VERSION 5.7 ;
  NOWIREEXTENSIONATPIN ON ;
  DIVIDERCHAR "/" ;
  BUSBITCHARS "[]" ;
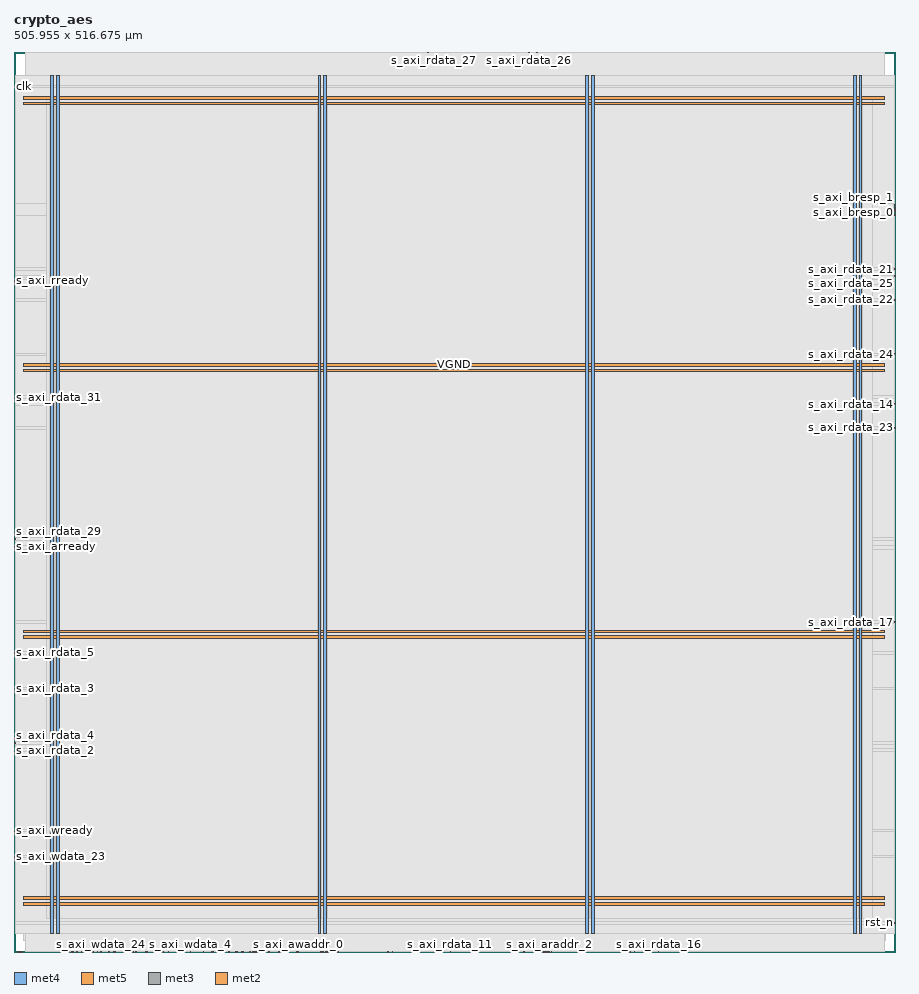
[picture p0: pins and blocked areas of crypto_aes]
MACRO crypto_aes
  CLASS BLOCK ;
  FOREIGN crypto_aes ;
  ORIGIN 0.000 0.000 ;
  SIZE 505.955 BY 516.675 ;
  PIN VGND
    DIRECTION INOUT ;
    USE GROUND ;
    PORT
      LAYER met4 ;
        RECT 24.340 10.640 25.940 503.440 ;
    END
    PORT
      LAYER met4 ;
        RECT 177.940 10.640 179.540 503.440 ;
    END
    PORT
      LAYER met4 ;
        RECT 331.540 10.640 333.140 503.440 ;
    END
    PORT
      LAYER met4 ;
        RECT 485.140 10.640 486.740 503.440 ;
    END
    PORT
      LAYER met5 ;
        RECT 5.520 30.030 500.020 31.630 ;
    END
    PORT
      LAYER met5 ;
        RECT 5.520 183.210 500.020 184.810 ;
    END
    PORT
      LAYER met5 ;
        RECT 5.520 336.390 500.020 337.990 ;
    END
    PORT
      LAYER met5 ;
        RECT 5.520 489.570 500.020 491.170 ;
    END
  END VGND
  PIN VPWR
    DIRECTION INOUT ;
    USE POWER ;
    PORT
      LAYER met4 ;
        RECT 21.040 10.640 22.640 503.440 ;
    END
    PORT
      LAYER met4 ;
        RECT 174.640 10.640 176.240 503.440 ;
    END
    PORT
      LAYER met4 ;
        RECT 328.240 10.640 329.840 503.440 ;
    END
    PORT
      LAYER met4 ;
        RECT 481.840 10.640 483.440 503.440 ;
    END
    PORT
      LAYER met5 ;
        RECT 5.520 26.730 500.020 28.330 ;
    END
    PORT
      LAYER met5 ;
        RECT 5.520 179.910 500.020 181.510 ;
    END
    PORT
      LAYER met5 ;
        RECT 5.520 333.090 500.020 334.690 ;
    END
    PORT
      LAYER met5 ;
        RECT 5.520 486.270 500.020 487.870 ;
    END
  END VPWR
  PIN clk
    DIRECTION INPUT ;
    USE SIGNAL ;
    ANTENNAGATEAREA 1.286700 ;
    ANTENNADIFFAREA 0.434700 ;
    PORT
      LAYER met3 ;
        RECT 0.000 496.440 0.600 497.040 ;
    END
  END clk
  PIN irq
    DIRECTION OUTPUT ;
    USE SIGNAL ;
    ANTENNAGATEAREA 0.434700 ;
    ANTENNADIFFAREA 1.137600 ;
    PORT
      LAYER met3 ;
        RECT 505.355 423.000 505.955 423.600 ;
    END
  END irq
  PIN rst_n
    DIRECTION INPUT ;
    USE SIGNAL ;
    ANTENNAGATEAREA 0.647700 ;
    ANTENNADIFFAREA 0.434700 ;
    PORT
      LAYER met3 ;
        RECT 505.355 16.360 505.955 16.960 ;
    END
  END rst_n
  PIN s_axi_araddr_0
    DIRECTION INPUT ;
    USE SIGNAL ;
    ANTENNAGATEAREA 0.647700 ;
    ANTENNADIFFAREA 0.434700 ;
    PORT
      LAYER met2 ;
        RECT 305.530 0.000 305.810 0.280 ;
    END
  END s_axi_araddr_0
  PIN s_axi_araddr_1
    DIRECTION INPUT ;
    USE SIGNAL ;
    ANTENNAGATEAREA 0.647700 ;
    ANTENNADIFFAREA 0.434700 ;
    PORT
      LAYER met2 ;
        RECT 306.450 0.000 306.730 0.280 ;
    END
  END s_axi_araddr_1
  PIN s_axi_araddr_10
    DIRECTION INPUT ;
    USE SIGNAL ;
    PORT
      LAYER met2 ;
        RECT 1.930 0.000 2.210 0.280 ;
    END
  END s_axi_araddr_10
  PIN s_axi_araddr_11
    DIRECTION INPUT ;
    USE SIGNAL ;
    PORT
      LAYER met2 ;
        RECT 2.850 0.000 3.130 0.280 ;
    END
  END s_axi_araddr_11
  PIN s_axi_araddr_2
    DIRECTION INPUT ;
    USE SIGNAL ;
    ANTENNAGATEAREA 0.647700 ;
    ANTENNADIFFAREA 0.434700 ;
    PORT
      LAYER met2 ;
        RECT 307.370 0.000 307.650 0.280 ;
    END
  END s_axi_araddr_2
  PIN s_axi_araddr_3
    DIRECTION INPUT ;
    USE SIGNAL ;
    ANTENNAGATEAREA 0.647700 ;
    ANTENNADIFFAREA 0.434700 ;
    PORT
      LAYER met2 ;
        RECT 308.290 0.000 308.570 0.280 ;
    END
  END s_axi_araddr_3
  PIN s_axi_araddr_4
    DIRECTION INPUT ;
    USE SIGNAL ;
    ANTENNAGATEAREA 0.647700 ;
    ANTENNADIFFAREA 0.434700 ;
    PORT
      LAYER met2 ;
        RECT 304.610 0.000 304.890 0.280 ;
    END
  END s_axi_araddr_4
  PIN s_axi_araddr_5
    DIRECTION INPUT ;
    USE SIGNAL ;
    ANTENNAGATEAREA 0.647700 ;
    ANTENNADIFFAREA 0.434700 ;
    PORT
      LAYER met2 ;
        RECT 301.850 0.000 302.130 0.280 ;
    END
  END s_axi_araddr_5
  PIN s_axi_araddr_6
    DIRECTION INPUT ;
    USE SIGNAL ;
    ANTENNAGATEAREA 0.647700 ;
    ANTENNADIFFAREA 0.434700 ;
    PORT
      LAYER met2 ;
        RECT 303.690 0.000 303.970 0.280 ;
    END
  END s_axi_araddr_6
  PIN s_axi_araddr_7
    DIRECTION INPUT ;
    USE SIGNAL ;
    ANTENNAGATEAREA 0.647700 ;
    ANTENNADIFFAREA 0.434700 ;
    PORT
      LAYER met2 ;
        RECT 302.770 0.000 303.050 0.280 ;
    END
  END s_axi_araddr_7
  PIN s_axi_araddr_8
    DIRECTION INPUT ;
    USE SIGNAL ;
    PORT
      LAYER met2 ;
        RECT 3.770 0.000 4.050 0.280 ;
    END
  END s_axi_araddr_8
  PIN s_axi_araddr_9
    DIRECTION INPUT ;
    USE SIGNAL ;
    PORT
      LAYER met2 ;
        RECT 4.690 0.000 4.970 0.280 ;
    END
  END s_axi_araddr_9
  PIN s_axi_arready
    DIRECTION OUTPUT ;
    USE SIGNAL ;
    ANTENNAGATEAREA 0.434700 ;
    ANTENNADIFFAREA 1.137600 ;
    PORT
      LAYER met3 ;
        RECT 0.000 232.600 0.600 233.200 ;
    END
  END s_axi_arready
  PIN s_axi_arvalid
    DIRECTION INPUT ;
    USE SIGNAL ;
    ANTENNAGATEAREA 0.647700 ;
    ANTENNADIFFAREA 0.434700 ;
    PORT
      LAYER met3 ;
        RECT 0.000 231.240 0.600 231.840 ;
    END
  END s_axi_arvalid
  PIN s_axi_awaddr_0
    DIRECTION INPUT ;
    USE SIGNAL ;
    ANTENNAGATEAREA 0.647700 ;
    ANTENNADIFFAREA 0.434700 ;
    PORT
      LAYER met2 ;
        RECT 162.930 0.000 163.210 0.280 ;
    END
  END s_axi_awaddr_0
  PIN s_axi_awaddr_1
    DIRECTION INPUT ;
    USE SIGNAL ;
    ANTENNAGATEAREA 0.647700 ;
    ANTENNADIFFAREA 0.434700 ;
    PORT
      LAYER met2 ;
        RECT 162.010 0.000 162.290 0.280 ;
    END
  END s_axi_awaddr_1
  PIN s_axi_awaddr_10
    DIRECTION INPUT ;
    USE SIGNAL ;
    ANTENNAGATEAREA 0.647700 ;
    ANTENNADIFFAREA 0.434700 ;
    PORT
      LAYER met2 ;
        RECT 146.370 0.000 146.650 0.280 ;
    END
  END s_axi_awaddr_10
  PIN s_axi_awaddr_11
    DIRECTION INPUT ;
    USE SIGNAL ;
    ANTENNAGATEAREA 0.647700 ;
    ANTENNADIFFAREA 0.434700 ;
    PORT
      LAYER met2 ;
        RECT 130.730 0.000 131.010 0.280 ;
    END
  END s_axi_awaddr_11
  PIN s_axi_awaddr_2
    DIRECTION INPUT ;
    USE SIGNAL ;
    ANTENNAGATEAREA 0.647700 ;
    ANTENNADIFFAREA 0.434700 ;
    PORT
      LAYER met2 ;
        RECT 154.650 0.000 154.930 0.280 ;
    END
  END s_axi_awaddr_2
  PIN s_axi_awaddr_3
    DIRECTION INPUT ;
    USE SIGNAL ;
    ANTENNAGATEAREA 0.647700 ;
    ANTENNADIFFAREA 0.434700 ;
    PORT
      LAYER met2 ;
        RECT 153.730 0.000 154.010 0.280 ;
    END
  END s_axi_awaddr_3
  PIN s_axi_awaddr_4
    DIRECTION INPUT ;
    USE SIGNAL ;
    ANTENNAGATEAREA 0.647700 ;
    ANTENNADIFFAREA 0.434700 ;
    PORT
      LAYER met2 ;
        RECT 178.570 0.000 178.850 0.280 ;
    END
  END s_axi_awaddr_4
  PIN s_axi_awaddr_5
    DIRECTION INPUT ;
    USE SIGNAL ;
    ANTENNAGATEAREA 0.647700 ;
    ANTENNADIFFAREA 0.434700 ;
    PORT
      LAYER met2 ;
        RECT 180.410 0.000 180.690 0.280 ;
    END
  END s_axi_awaddr_5
  PIN s_axi_awaddr_6
    DIRECTION INPUT ;
    USE SIGNAL ;
    ANTENNAGATEAREA 0.647700 ;
    ANTENNADIFFAREA 0.434700 ;
    PORT
      LAYER met2 ;
        RECT 176.730 0.000 177.010 0.280 ;
    END
  END s_axi_awaddr_6
  PIN s_axi_awaddr_7
    DIRECTION INPUT ;
    USE SIGNAL ;
    ANTENNAGATEAREA 0.647700 ;
    ANTENNADIFFAREA 0.434700 ;
    PORT
      LAYER met2 ;
        RECT 177.650 0.000 177.930 0.280 ;
    END
  END s_axi_awaddr_7
  PIN s_axi_awaddr_8
    DIRECTION INPUT ;
    USE SIGNAL ;
    ANTENNAGATEAREA 0.647700 ;
    ANTENNADIFFAREA 0.434700 ;
    PORT
      LAYER met2 ;
        RECT 139.930 0.000 140.210 0.280 ;
    END
  END s_axi_awaddr_8
  PIN s_axi_awaddr_9
    DIRECTION INPUT ;
    USE SIGNAL ;
    ANTENNAGATEAREA 0.647700 ;
    ANTENNADIFFAREA 0.434700 ;
    PORT
      LAYER met2 ;
        RECT 131.650 0.000 131.930 0.280 ;
    END
  END s_axi_awaddr_9
  PIN s_axi_awready
    DIRECTION OUTPUT ;
    USE SIGNAL ;
    ANTENNAGATEAREA 0.434700 ;
    ANTENNADIFFAREA 1.137600 ;
    PORT
      LAYER met2 ;
        RECT 151.890 0.000 152.170 0.280 ;
    END
  END s_axi_awready
  PIN s_axi_awvalid
    DIRECTION INPUT ;
    USE SIGNAL ;
    ANTENNAGATEAREA 0.647700 ;
    ANTENNADIFFAREA 0.434700 ;
    PORT
      LAYER met2 ;
        RECT 139.010 0.000 139.290 0.280 ;
    END
  END s_axi_awvalid
  PIN s_axi_bready
    DIRECTION INPUT ;
    USE SIGNAL ;
    ANTENNAGATEAREA 0.647700 ;
    ANTENNADIFFAREA 0.434700 ;
    PORT
      LAYER met2 ;
        RECT 135.330 0.000 135.610 0.280 ;
    END
  END s_axi_bready
  PIN s_axi_bresp_0
    DIRECTION OUTPUT ;
    USE SIGNAL ;
    ANTENNAGATEAREA 0.434700 ;
    ANTENNADIFFAREA 0.434700 ;
    PORT
      LAYER met3 ;
        RECT 505.355 424.360 505.955 424.960 ;
    END
  END s_axi_bresp_0
  PIN s_axi_bresp_1
    DIRECTION OUTPUT ;
    USE SIGNAL ;
    ANTENNAGATEAREA 0.434700 ;
    ANTENNADIFFAREA 0.775300 ;
    PORT
      LAYER met3 ;
        RECT 505.355 428.440 505.955 429.040 ;
    END
  END s_axi_bresp_1
  PIN s_axi_bvalid
    DIRECTION OUTPUT ;
    USE SIGNAL ;
    ANTENNAGATEAREA 0.434700 ;
    ANTENNADIFFAREA 1.137600 ;
    PORT
      LAYER met2 ;
        RECT 127.970 0.000 128.250 0.280 ;
    END
  END s_axi_bvalid
  PIN s_axi_rdata_0
    DIRECTION OUTPUT ;
    USE SIGNAL ;
    ANTENNAGATEAREA 0.434700 ;
    ANTENNADIFFAREA 1.137600 ;
    PORT
      LAYER met2 ;
        RECT 175.810 0.000 176.090 0.280 ;
    END
  END s_axi_rdata_0
  PIN s_axi_rdata_1
    DIRECTION OUTPUT ;
    USE SIGNAL ;
    ANTENNAGATEAREA 0.434700 ;
    ANTENNADIFFAREA 1.137600 ;
    PORT
      LAYER met2 ;
        RECT 265.050 0.000 265.330 0.280 ;
    END
  END s_axi_rdata_1
  PIN s_axi_rdata_10
    DIRECTION OUTPUT ;
    USE SIGNAL ;
    ANTENNAGATEAREA 0.434700 ;
    ANTENNADIFFAREA 1.137600 ;
    PORT
      LAYER met2 ;
        RECT 353.370 0.000 353.650 0.280 ;
    END
  END s_axi_rdata_10
  PIN s_axi_rdata_11
    DIRECTION OUTPUT ;
    USE SIGNAL ;
    ANTENNAGATEAREA 0.434700 ;
    ANTENNADIFFAREA 1.137600 ;
    PORT
      LAYER met2 ;
        RECT 250.330 0.000 250.610 0.280 ;
    END
  END s_axi_rdata_11
  PIN s_axi_rdata_12
    DIRECTION OUTPUT ;
    USE SIGNAL ;
    ANTENNAGATEAREA 0.434700 ;
    ANTENNADIFFAREA 1.137600 ;
    PORT
      LAYER met2 ;
        RECT 179.490 0.000 179.770 0.280 ;
    END
  END s_axi_rdata_12
  PIN s_axi_rdata_13
    DIRECTION OUTPUT ;
    USE SIGNAL ;
    ANTENNAGATEAREA 0.434700 ;
    ANTENNADIFFAREA 1.137600 ;
    PORT
      LAYER met2 ;
        RECT 356.130 0.000 356.410 0.280 ;
    END
  END s_axi_rdata_13
  PIN s_axi_rdata_14
    DIRECTION OUTPUT ;
    USE SIGNAL ;
    ANTENNAGATEAREA 0.434700 ;
    ANTENNADIFFAREA 1.137600 ;
    PORT
      LAYER met3 ;
        RECT 505.355 314.200 505.955 314.800 ;
    END
  END s_axi_rdata_14
  PIN s_axi_rdata_15
    DIRECTION OUTPUT ;
    USE SIGNAL ;
    ANTENNAGATEAREA 0.434700 ;
    ANTENNADIFFAREA 1.137600 ;
    PORT
      LAYER met2 ;
        RECT 214.450 0.000 214.730 0.280 ;
    END
  END s_axi_rdata_15
  PIN s_axi_rdata_16
    DIRECTION OUTPUT ;
    USE SIGNAL ;
    ANTENNAGATEAREA 0.434700 ;
    ANTENNADIFFAREA 1.137600 ;
    PORT
      LAYER met2 ;
        RECT 369.930 0.000 370.210 0.280 ;
    END
  END s_axi_rdata_16
  PIN s_axi_rdata_17
    DIRECTION OUTPUT ;
    USE SIGNAL ;
    ANTENNAGATEAREA 0.434700 ;
    ANTENNADIFFAREA 1.137600 ;
    PORT
      LAYER met3 ;
        RECT 505.355 189.080 505.955 189.680 ;
    END
  END s_axi_rdata_17
  PIN s_axi_rdata_18
    DIRECTION OUTPUT ;
    USE SIGNAL ;
    ANTENNAGATEAREA 0.434700 ;
    ANTENNADIFFAREA 1.137600 ;
    PORT
      LAYER met2 ;
        RECT 286.210 0.000 286.490 0.280 ;
    END
  END s_axi_rdata_18
  PIN s_axi_rdata_19
    DIRECTION OUTPUT ;
    USE SIGNAL ;
    ANTENNAGATEAREA 0.434700 ;
    ANTENNADIFFAREA 1.137600 ;
    PORT
      LAYER met2 ;
        RECT 245.730 0.000 246.010 0.280 ;
    END
  END s_axi_rdata_19
  PIN s_axi_rdata_2
    DIRECTION OUTPUT ;
    USE SIGNAL ;
    ANTENNAGATEAREA 0.434700 ;
    ANTENNADIFFAREA 1.137600 ;
    PORT
      LAYER met3 ;
        RECT 0.000 115.640 0.600 116.240 ;
    END
  END s_axi_rdata_2
  PIN s_axi_rdata_20
    DIRECTION OUTPUT ;
    USE SIGNAL ;
    ANTENNAGATEAREA 0.434700 ;
    ANTENNADIFFAREA 1.137600 ;
    PORT
      LAYER met2 ;
        RECT 292.650 0.000 292.930 0.280 ;
    END
  END s_axi_rdata_20
  PIN s_axi_rdata_21
    DIRECTION OUTPUT ;
    USE SIGNAL ;
    ANTENNAGATEAREA 0.434700 ;
    ANTENNADIFFAREA 1.137600 ;
    PORT
      LAYER met3 ;
        RECT 505.355 391.720 505.955 392.320 ;
    END
  END s_axi_rdata_21
  PIN s_axi_rdata_22
    DIRECTION OUTPUT ;
    USE SIGNAL ;
    ANTENNAGATEAREA 0.434700 ;
    ANTENNADIFFAREA 1.137600 ;
    PORT
      LAYER met3 ;
        RECT 505.355 374.040 505.955 374.640 ;
    END
  END s_axi_rdata_22
  PIN s_axi_rdata_23
    DIRECTION OUTPUT ;
    USE SIGNAL ;
    ANTENNAGATEAREA 0.434700 ;
    ANTENNADIFFAREA 1.137600 ;
    PORT
      LAYER met3 ;
        RECT 505.355 300.600 505.955 301.200 ;
    END
  END s_axi_rdata_23
  PIN s_axi_rdata_24
    DIRECTION OUTPUT ;
    USE SIGNAL ;
    ANTENNAGATEAREA 0.434700 ;
    ANTENNADIFFAREA 1.137600 ;
    PORT
      LAYER met3 ;
        RECT 505.355 342.760 505.955 343.360 ;
    END
  END s_axi_rdata_24
  PIN s_axi_rdata_25
    DIRECTION OUTPUT ;
    USE SIGNAL ;
    ANTENNAGATEAREA 0.434700 ;
    ANTENNADIFFAREA 1.137600 ;
    PORT
      LAYER met3 ;
        RECT 505.355 387.640 505.955 388.240 ;
    END
  END s_axi_rdata_25
  PIN s_axi_rdata_26
    DIRECTION OUTPUT ;
    USE SIGNAL ;
    ANTENNAGATEAREA 0.434700 ;
    ANTENNADIFFAREA 1.137600 ;
    PORT
      LAYER met2 ;
        RECT 295.410 516.395 295.690 516.675 ;
    END
  END s_axi_rdata_26
  PIN s_axi_rdata_27
    DIRECTION OUTPUT ;
    USE SIGNAL ;
    ANTENNAGATEAREA 0.434700 ;
    ANTENNADIFFAREA 1.137600 ;
    PORT
      LAYER met2 ;
        RECT 241.130 516.395 241.410 516.675 ;
    END
  END s_axi_rdata_27
  PIN s_axi_rdata_28
    DIRECTION OUTPUT ;
    USE SIGNAL ;
    ANTENNAGATEAREA 0.434700 ;
    ANTENNADIFFAREA 1.137600 ;
    PORT
      LAYER met2 ;
        RECT 196.970 516.395 197.250 516.675 ;
    END
  END s_axi_rdata_28
  PIN s_axi_rdata_29
    DIRECTION OUTPUT ;
    USE SIGNAL ;
    ANTENNAGATEAREA 0.434700 ;
    ANTENNADIFFAREA 1.137600 ;
    PORT
      LAYER met3 ;
        RECT 0.000 236.680 0.600 237.280 ;
    END
  END s_axi_rdata_29
  PIN s_axi_rdata_3
    DIRECTION OUTPUT ;
    USE SIGNAL ;
    ANTENNAGATEAREA 0.434700 ;
    ANTENNADIFFAREA 1.137600 ;
    PORT
      LAYER met3 ;
        RECT 0.000 151.000 0.600 151.600 ;
    END
  END s_axi_rdata_3
  PIN s_axi_rdata_30
    DIRECTION OUTPUT ;
    USE SIGNAL ;
    ANTENNAGATEAREA 0.434700 ;
    ANTENNADIFFAREA 1.137600 ;
    PORT
      LAYER met3 ;
        RECT 0.000 383.560 0.600 384.160 ;
    END
  END s_axi_rdata_30
  PIN s_axi_rdata_31
    DIRECTION OUTPUT ;
    USE SIGNAL ;
    ANTENNAGATEAREA 0.434700 ;
    ANTENNADIFFAREA 1.137600 ;
    PORT
      LAYER met3 ;
        RECT 0.000 318.280 0.600 318.880 ;
    END
  END s_axi_rdata_31
  PIN s_axi_rdata_4
    DIRECTION OUTPUT ;
    USE SIGNAL ;
    ANTENNAGATEAREA 0.434700 ;
    ANTENNADIFFAREA 1.137600 ;
    PORT
      LAYER met3 ;
        RECT 0.000 119.720 0.600 120.320 ;
    END
  END s_axi_rdata_4
  PIN s_axi_rdata_5
    DIRECTION OUTPUT ;
    USE SIGNAL ;
    ANTENNAGATEAREA 0.434700 ;
    ANTENNADIFFAREA 1.137600 ;
    PORT
      LAYER met3 ;
        RECT 0.000 171.400 0.600 172.000 ;
    END
  END s_axi_rdata_5
  PIN s_axi_rdata_6
    DIRECTION OUTPUT ;
    USE SIGNAL ;
    ANTENNAGATEAREA 0.434700 ;
    ANTENNADIFFAREA 1.137600 ;
    PORT
      LAYER met2 ;
        RECT 237.450 516.395 237.730 516.675 ;
    END
  END s_axi_rdata_6
  PIN s_axi_rdata_7
    DIRECTION OUTPUT ;
    USE SIGNAL ;
    ANTENNAGATEAREA 0.434700 ;
    ANTENNADIFFAREA 1.137600 ;
    PORT
      LAYER met2 ;
        RECT 217.210 0.000 217.490 0.280 ;
    END
  END s_axi_rdata_7
  PIN s_axi_rdata_8
    DIRECTION OUTPUT ;
    USE SIGNAL ;
    ANTENNAGATEAREA 0.434700 ;
    ANTENNADIFFAREA 1.137600 ;
    PORT
      LAYER met2 ;
        RECT 300.010 516.395 300.290 516.675 ;
    END
  END s_axi_rdata_8
  PIN s_axi_rdata_9
    DIRECTION OUTPUT ;
    USE SIGNAL ;
    ANTENNAGATEAREA 0.434700 ;
    ANTENNADIFFAREA 1.137600 ;
    PORT
      LAYER met2 ;
        RECT 288.970 0.000 289.250 0.280 ;
    END
  END s_axi_rdata_9
  PIN s_axi_rready
    DIRECTION INPUT ;
    USE SIGNAL ;
    ANTENNAGATEAREA 0.647700 ;
    ANTENNADIFFAREA 0.434700 ;
    PORT
      LAYER met3 ;
        RECT 0.000 384.920 0.600 385.520 ;
    END
  END s_axi_rready
  PIN s_axi_rresp_0
    DIRECTION OUTPUT ;
    USE SIGNAL ;
    ANTENNAGATEAREA 0.434700 ;
    ANTENNADIFFAREA 0.775300 ;
    PORT
      LAYER met3 ;
        RECT 505.355 425.720 505.955 426.320 ;
    END
  END s_axi_rresp_0
  PIN s_axi_rresp_1
    DIRECTION OUTPUT ;
    USE SIGNAL ;
    ANTENNAGATEAREA 0.434700 ;
    ANTENNADIFFAREA 0.775300 ;
    PORT
      LAYER met3 ;
        RECT 505.355 427.080 505.955 427.680 ;
    END
  END s_axi_rresp_1
  PIN s_axi_rvalid
    DIRECTION OUTPUT ;
    USE SIGNAL ;
    ANTENNAGATEAREA 0.434700 ;
    ANTENNADIFFAREA 1.137600 ;
    PORT
      LAYER met2 ;
        RECT 185.930 0.000 186.210 0.280 ;
    END
  END s_axi_rvalid
  PIN s_axi_wdata_0
    DIRECTION INPUT ;
    USE SIGNAL ;
    ANTENNAGATEAREA 0.647700 ;
    ANTENNADIFFAREA 0.434700 ;
    PORT
      LAYER met2 ;
        RECT 140.850 0.000 141.130 0.280 ;
    END
  END s_axi_wdata_0
  PIN s_axi_wdata_1
    DIRECTION INPUT ;
    USE SIGNAL ;
    ANTENNAGATEAREA 0.647700 ;
    ANTENNADIFFAREA 0.434700 ;
    PORT
      LAYER met2 ;
        RECT 142.690 0.000 142.970 0.280 ;
    END
  END s_axi_wdata_1
  PIN s_axi_wdata_10
    DIRECTION INPUT ;
    USE SIGNAL ;
    ANTENNAGATEAREA 0.647700 ;
    ANTENNADIFFAREA 0.434700 ;
    PORT
      LAYER met2 ;
        RECT 57.130 0.000 57.410 0.280 ;
    END
  END s_axi_wdata_10
  PIN s_axi_wdata_11
    DIRECTION INPUT ;
    USE SIGNAL ;
    ANTENNAGATEAREA 0.647700 ;
    ANTENNADIFFAREA 0.434700 ;
    PORT
      LAYER met2 ;
        RECT 47.930 0.000 48.210 0.280 ;
    END
  END s_axi_wdata_11
  PIN s_axi_wdata_12
    DIRECTION INPUT ;
    USE SIGNAL ;
    ANTENNAGATEAREA 0.647700 ;
    ANTENNADIFFAREA 0.434700 ;
    PORT
      LAYER met2 ;
        RECT 70.010 0.000 70.290 0.280 ;
    END
  END s_axi_wdata_12
  PIN s_axi_wdata_13
    DIRECTION INPUT ;
    USE SIGNAL ;
    ANTENNAGATEAREA 0.647700 ;
    ANTENNADIFFAREA 0.434700 ;
    PORT
      LAYER met2 ;
        RECT 88.410 0.000 88.690 0.280 ;
    END
  END s_axi_wdata_13
  PIN s_axi_wdata_14
    DIRECTION INPUT ;
    USE SIGNAL ;
    ANTENNAGATEAREA 0.647700 ;
    ANTENNADIFFAREA 0.434700 ;
    PORT
      LAYER met2 ;
        RECT 84.730 0.000 85.010 0.280 ;
    END
  END s_axi_wdata_14
  PIN s_axi_wdata_15
    DIRECTION INPUT ;
    USE SIGNAL ;
    ANTENNAGATEAREA 0.647700 ;
    ANTENNADIFFAREA 0.434700 ;
    PORT
      LAYER met2 ;
        RECT 40.570 0.000 40.850 0.280 ;
    END
  END s_axi_wdata_15
  PIN s_axi_wdata_16
    DIRECTION INPUT ;
    USE SIGNAL ;
    ANTENNAGATEAREA 0.647700 ;
    ANTENNADIFFAREA 0.434700 ;
    PORT
      LAYER met2 ;
        RECT 123.370 0.000 123.650 0.280 ;
    END
  END s_axi_wdata_16
  PIN s_axi_wdata_17
    DIRECTION INPUT ;
    USE SIGNAL ;
    ANTENNAGATEAREA 0.647700 ;
    ANTENNADIFFAREA 0.434700 ;
    PORT
      LAYER met2 ;
        RECT 35.970 0.000 36.250 0.280 ;
    END
  END s_axi_wdata_17
  PIN s_axi_wdata_18
    DIRECTION INPUT ;
    USE SIGNAL ;
    ANTENNAGATEAREA 0.647700 ;
    ANTENNADIFFAREA 0.434700 ;
    PORT
      LAYER met2 ;
        RECT 108.650 0.000 108.930 0.280 ;
    END
  END s_axi_wdata_18
  PIN s_axi_wdata_19
    DIRECTION INPUT ;
    USE SIGNAL ;
    ANTENNAGATEAREA 0.647700 ;
    ANTENNADIFFAREA 0.434700 ;
    PORT
      LAYER met2 ;
        RECT 97.610 0.000 97.890 0.280 ;
    END
  END s_axi_wdata_19
  PIN s_axi_wdata_2
    DIRECTION INPUT ;
    USE SIGNAL ;
    ANTENNAGATEAREA 0.647700 ;
    ANTENNADIFFAREA 0.434700 ;
    PORT
      LAYER met2 ;
        RECT 137.170 0.000 137.450 0.280 ;
    END
  END s_axi_wdata_2
  PIN s_axi_wdata_20
    DIRECTION INPUT ;
    USE SIGNAL ;
    ANTENNAGATEAREA 0.647700 ;
    ANTENNADIFFAREA 0.434700 ;
    PORT
      LAYER met2 ;
        RECT 54.370 0.000 54.650 0.280 ;
    END
  END s_axi_wdata_20
  PIN s_axi_wdata_21
    DIRECTION INPUT ;
    USE SIGNAL ;
    ANTENNAGATEAREA 0.647700 ;
    ANTENNADIFFAREA 0.434700 ;
    PORT
      LAYER met2 ;
        RECT 62.650 0.000 62.930 0.280 ;
    END
  END s_axi_wdata_21
  PIN s_axi_wdata_22
    DIRECTION INPUT ;
    USE SIGNAL ;
    ANTENNAGATEAREA 0.647700 ;
    ANTENNADIFFAREA 0.434700 ;
    PORT
      LAYER met2 ;
        RECT 85.650 0.000 85.930 0.280 ;
    END
  END s_axi_wdata_22
  PIN s_axi_wdata_23
    DIRECTION INPUT ;
    USE SIGNAL ;
    ANTENNAGATEAREA 0.647700 ;
    ANTENNADIFFAREA 0.434700 ;
    PORT
      LAYER met3 ;
        RECT 0.000 54.440 0.600 55.040 ;
    END
  END s_axi_wdata_23
  PIN s_axi_wdata_24
    DIRECTION INPUT ;
    USE SIGNAL ;
    ANTENNAGATEAREA 0.647700 ;
    ANTENNADIFFAREA 0.434700 ;
    PORT
      LAYER met2 ;
        RECT 49.770 0.000 50.050 0.280 ;
    END
  END s_axi_wdata_24
  PIN s_axi_wdata_25
    DIRECTION INPUT ;
    USE SIGNAL ;
    ANTENNAGATEAREA 0.647700 ;
    ANTENNADIFFAREA 0.434700 ;
    PORT
      LAYER met2 ;
        RECT 45.170 0.000 45.450 0.280 ;
    END
  END s_axi_wdata_25
  PIN s_axi_wdata_26
    DIRECTION INPUT ;
    USE SIGNAL ;
    ANTENNAGATEAREA 0.647700 ;
    ANTENNADIFFAREA 0.434700 ;
    PORT
      LAYER met2 ;
        RECT 113.250 0.000 113.530 0.280 ;
    END
  END s_axi_wdata_26
  PIN s_axi_wdata_27
    DIRECTION INPUT ;
    USE SIGNAL ;
    ANTENNAGATEAREA 0.647700 ;
    ANTENNADIFFAREA 0.434700 ;
    PORT
      LAYER met2 ;
        RECT 38.730 0.000 39.010 0.280 ;
    END
  END s_axi_wdata_27
  PIN s_axi_wdata_28
    DIRECTION INPUT ;
    USE SIGNAL ;
    ANTENNAGATEAREA 0.647700 ;
    ANTENNADIFFAREA 0.434700 ;
    PORT
      LAYER met2 ;
        RECT 117.850 0.000 118.130 0.280 ;
    END
  END s_axi_wdata_28
  PIN s_axi_wdata_29
    DIRECTION INPUT ;
    USE SIGNAL ;
    ANTENNAGATEAREA 0.647700 ;
    ANTENNADIFFAREA 0.434700 ;
    PORT
      LAYER met2 ;
        RECT 114.170 0.000 114.450 0.280 ;
    END
  END s_axi_wdata_29
  PIN s_axi_wdata_3
    DIRECTION INPUT ;
    USE SIGNAL ;
    ANTENNAGATEAREA 0.647700 ;
    ANTENNADIFFAREA 0.434700 ;
    PORT
      LAYER met2 ;
        RECT 43.330 0.000 43.610 0.280 ;
    END
  END s_axi_wdata_3
  PIN s_axi_wdata_30
    DIRECTION INPUT ;
    USE SIGNAL ;
    ANTENNAGATEAREA 0.647700 ;
    ANTENNADIFFAREA 0.434700 ;
    PORT
      LAYER met2 ;
        RECT 34.130 0.000 34.410 0.280 ;
    END
  END s_axi_wdata_30
  PIN s_axi_wdata_31
    DIRECTION INPUT ;
    USE SIGNAL ;
    ANTENNAGATEAREA 0.647700 ;
    ANTENNADIFFAREA 0.434700 ;
    PORT
      LAYER met2 ;
        RECT 81.970 0.000 82.250 0.280 ;
    END
  END s_axi_wdata_31
  PIN s_axi_wdata_4
    DIRECTION INPUT ;
    USE SIGNAL ;
    ANTENNAGATEAREA 0.647700 ;
    ANTENNADIFFAREA 0.434700 ;
    PORT
      LAYER met2 ;
        RECT 101.290 0.000 101.570 0.280 ;
    END
  END s_axi_wdata_4
  PIN s_axi_wdata_5
    DIRECTION INPUT ;
    USE SIGNAL ;
    ANTENNAGATEAREA 0.647700 ;
    ANTENNADIFFAREA 0.434700 ;
    PORT
      LAYER met2 ;
        RECT 58.050 0.000 58.330 0.280 ;
    END
  END s_axi_wdata_5
  PIN s_axi_wdata_6
    DIRECTION INPUT ;
    USE SIGNAL ;
    ANTENNAGATEAREA 0.647700 ;
    ANTENNADIFFAREA 0.434700 ;
    PORT
      LAYER met2 ;
        RECT 75.530 0.000 75.810 0.280 ;
    END
  END s_axi_wdata_6
  PIN s_axi_wdata_7
    DIRECTION INPUT ;
    USE SIGNAL ;
    ANTENNAGATEAREA 0.647700 ;
    ANTENNADIFFAREA 0.434700 ;
    PORT
      LAYER met2 ;
        RECT 65.410 0.000 65.690 0.280 ;
    END
  END s_axi_wdata_7
  PIN s_axi_wdata_8
    DIRECTION INPUT ;
    USE SIGNAL ;
    ANTENNAGATEAREA 0.647700 ;
    ANTENNADIFFAREA 0.434700 ;
    PORT
      LAYER met2 ;
        RECT 76.450 0.000 76.730 0.280 ;
    END
  END s_axi_wdata_8
  PIN s_axi_wdata_9
    DIRECTION INPUT ;
    USE SIGNAL ;
    ANTENNAGATEAREA 0.647700 ;
    ANTENNADIFFAREA 0.434700 ;
    PORT
      LAYER met2 ;
        RECT 33.210 0.000 33.490 0.280 ;
    END
  END s_axi_wdata_9
  PIN s_axi_wready
    DIRECTION OUTPUT ;
    USE SIGNAL ;
    ANTENNAGATEAREA 0.434700 ;
    ANTENNADIFFAREA 1.137600 ;
    PORT
      LAYER met3 ;
        RECT 0.000 69.400 0.600 70.000 ;
    END
  END s_axi_wready
  PIN s_axi_wstrb_0
    DIRECTION INPUT ;
    USE SIGNAL ;
    ANTENNAGATEAREA 0.647700 ;
    ANTENNADIFFAREA 0.434700 ;
    PORT
      LAYER met2 ;
        RECT 138.090 0.000 138.370 0.280 ;
    END
  END s_axi_wstrb_0
  PIN s_axi_wstrb_1
    DIRECTION INPUT ;
    USE SIGNAL ;
    ANTENNAGATEAREA 0.647700 ;
    ANTENNADIFFAREA 0.434700 ;
    PORT
      LAYER met2 ;
        RECT 68.170 0.000 68.450 0.280 ;
    END
  END s_axi_wstrb_1
  PIN s_axi_wstrb_2
    DIRECTION INPUT ;
    USE SIGNAL ;
    ANTENNAGATEAREA 0.647700 ;
    ANTENNADIFFAREA 0.434700 ;
    PORT
      LAYER met2 ;
        RECT 63.570 0.000 63.850 0.280 ;
    END
  END s_axi_wstrb_2
  PIN s_axi_wstrb_3
    DIRECTION INPUT ;
    USE SIGNAL ;
    ANTENNAGATEAREA 0.647700 ;
    ANTENNADIFFAREA 0.434700 ;
    PORT
      LAYER met2 ;
        RECT 31.370 0.000 31.650 0.280 ;
    END
  END s_axi_wstrb_3
  PIN s_axi_wvalid
    DIRECTION INPUT ;
    USE SIGNAL ;
    ANTENNAGATEAREA 0.647700 ;
    ANTENNADIFFAREA 0.434700 ;
    PORT
      LAYER met2 ;
        RECT 127.050 0.000 127.330 0.280 ;
    END
  END s_axi_wvalid
  OBS
      LAYER nwell ;
        RECT 5.330 10.795 500.210 503.390 ;
      LAYER li1 ;
        RECT 5.520 10.795 500.020 503.285 ;
      LAYER met1 ;
        RECT 5.520 6.500 500.320 503.440 ;
      LAYER met2 ;
        RECT 6.530 516.115 196.690 516.395 ;
        RECT 197.530 516.115 237.170 516.395 ;
        RECT 238.010 516.115 240.850 516.395 ;
        RECT 241.690 516.115 295.130 516.395 ;
        RECT 295.970 516.115 299.730 516.395 ;
        RECT 300.570 516.115 499.460 516.395 ;
        RECT 6.530 0.560 499.460 516.115 ;
        RECT 6.530 0.070 31.090 0.560 ;
        RECT 31.930 0.070 32.930 0.560 ;
        RECT 33.770 0.070 33.850 0.560 ;
        RECT 34.690 0.070 35.690 0.560 ;
        RECT 36.530 0.070 38.450 0.560 ;
        RECT 39.290 0.070 40.290 0.560 ;
        RECT 41.130 0.070 43.050 0.560 ;
        RECT 43.890 0.070 44.890 0.560 ;
        RECT 45.730 0.070 47.650 0.560 ;
        RECT 48.490 0.070 49.490 0.560 ;
        RECT 50.330 0.070 54.090 0.560 ;
        RECT 54.930 0.070 56.850 0.560 ;
        RECT 57.690 0.070 57.770 0.560 ;
        RECT 58.610 0.070 62.370 0.560 ;
        RECT 63.210 0.070 63.290 0.560 ;
        RECT 64.130 0.070 65.130 0.560 ;
        RECT 65.970 0.070 67.890 0.560 ;
        RECT 68.730 0.070 69.730 0.560 ;
        RECT 70.570 0.070 75.250 0.560 ;
        RECT 76.090 0.070 76.170 0.560 ;
        RECT 77.010 0.070 81.690 0.560 ;
        RECT 82.530 0.070 84.450 0.560 ;
        RECT 85.290 0.070 85.370 0.560 ;
        RECT 86.210 0.070 88.130 0.560 ;
        RECT 88.970 0.070 97.330 0.560 ;
        RECT 98.170 0.070 101.010 0.560 ;
        RECT 101.850 0.070 108.370 0.560 ;
        RECT 109.210 0.070 112.970 0.560 ;
        RECT 113.810 0.070 113.890 0.560 ;
        RECT 114.730 0.070 117.570 0.560 ;
        RECT 118.410 0.070 123.090 0.560 ;
        RECT 123.930 0.070 126.770 0.560 ;
        RECT 127.610 0.070 127.690 0.560 ;
        RECT 128.530 0.070 130.450 0.560 ;
        RECT 131.290 0.070 131.370 0.560 ;
        RECT 132.210 0.070 135.050 0.560 ;
        RECT 135.890 0.070 136.890 0.560 ;
        RECT 137.730 0.070 137.810 0.560 ;
        RECT 138.650 0.070 138.730 0.560 ;
        RECT 139.570 0.070 139.650 0.560 ;
        RECT 140.490 0.070 140.570 0.560 ;
        RECT 141.410 0.070 142.410 0.560 ;
        RECT 143.250 0.070 146.090 0.560 ;
        RECT 146.930 0.070 151.610 0.560 ;
        RECT 152.450 0.070 153.450 0.560 ;
        RECT 154.290 0.070 154.370 0.560 ;
        RECT 155.210 0.070 161.730 0.560 ;
        RECT 162.570 0.070 162.650 0.560 ;
        RECT 163.490 0.070 175.530 0.560 ;
        RECT 176.370 0.070 176.450 0.560 ;
        RECT 177.290 0.070 177.370 0.560 ;
        RECT 178.210 0.070 178.290 0.560 ;
        RECT 179.130 0.070 179.210 0.560 ;
        RECT 180.050 0.070 180.130 0.560 ;
        RECT 180.970 0.070 185.650 0.560 ;
        RECT 186.490 0.070 214.170 0.560 ;
        RECT 215.010 0.070 216.930 0.560 ;
        RECT 217.770 0.070 245.450 0.560 ;
        RECT 246.290 0.070 250.050 0.560 ;
        RECT 250.890 0.070 264.770 0.560 ;
        RECT 265.610 0.070 285.930 0.560 ;
        RECT 286.770 0.070 288.690 0.560 ;
        RECT 289.530 0.070 292.370 0.560 ;
        RECT 293.210 0.070 301.570 0.560 ;
        RECT 302.410 0.070 302.490 0.560 ;
        RECT 303.330 0.070 303.410 0.560 ;
        RECT 304.250 0.070 304.330 0.560 ;
        RECT 305.170 0.070 305.250 0.560 ;
        RECT 306.090 0.070 306.170 0.560 ;
        RECT 307.010 0.070 307.090 0.560 ;
        RECT 307.930 0.070 308.010 0.560 ;
        RECT 308.850 0.070 353.090 0.560 ;
        RECT 353.930 0.070 355.850 0.560 ;
        RECT 356.690 0.070 369.650 0.560 ;
        RECT 370.490 0.070 499.460 0.560 ;
      LAYER met3 ;
        RECT 0.600 497.440 505.355 503.365 ;
        RECT 1.000 496.040 505.355 497.440 ;
        RECT 0.600 429.440 505.355 496.040 ;
        RECT 0.600 422.600 504.955 429.440 ;
        RECT 0.600 392.720 505.355 422.600 ;
        RECT 0.600 391.320 504.955 392.720 ;
        RECT 0.600 388.640 505.355 391.320 ;
        RECT 0.600 387.240 504.955 388.640 ;
        RECT 0.600 385.920 505.355 387.240 ;
        RECT 1.000 383.160 505.355 385.920 ;
        RECT 0.600 375.040 505.355 383.160 ;
        RECT 0.600 373.640 504.955 375.040 ;
        RECT 0.600 343.760 505.355 373.640 ;
        RECT 0.600 342.360 504.955 343.760 ;
        RECT 0.600 319.280 505.355 342.360 ;
        RECT 1.000 317.880 505.355 319.280 ;
        RECT 0.600 315.200 505.355 317.880 ;
        RECT 0.600 313.800 504.955 315.200 ;
        RECT 0.600 301.600 505.355 313.800 ;
        RECT 0.600 300.200 504.955 301.600 ;
        RECT 0.600 237.680 505.355 300.200 ;
        RECT 1.000 236.280 505.355 237.680 ;
        RECT 0.600 233.600 505.355 236.280 ;
        RECT 1.000 230.840 505.355 233.600 ;
        RECT 0.600 190.080 505.355 230.840 ;
        RECT 0.600 188.680 504.955 190.080 ;
        RECT 0.600 172.400 505.355 188.680 ;
        RECT 1.000 171.000 505.355 172.400 ;
        RECT 0.600 152.000 505.355 171.000 ;
        RECT 1.000 150.600 505.355 152.000 ;
        RECT 0.600 120.720 505.355 150.600 ;
        RECT 1.000 119.320 505.355 120.720 ;
        RECT 0.600 116.640 505.355 119.320 ;
        RECT 1.000 115.240 505.355 116.640 ;
        RECT 0.600 70.400 505.355 115.240 ;
        RECT 1.000 69.000 505.355 70.400 ;
        RECT 0.600 55.440 505.355 69.000 ;
        RECT 1.000 54.040 505.355 55.440 ;
        RECT 0.600 17.360 505.355 54.040 ;
        RECT 0.600 15.960 504.955 17.360 ;
        RECT 0.600 10.715 505.355 15.960 ;
      LAYER met4 ;
        RECT 18.695 19.215 20.640 490.105 ;
        RECT 23.040 19.215 23.940 490.105 ;
        RECT 26.340 19.215 174.240 490.105 ;
        RECT 176.640 19.215 177.540 490.105 ;
        RECT 179.940 19.215 327.840 490.105 ;
        RECT 330.240 19.215 331.140 490.105 ;
        RECT 333.540 19.215 481.440 490.105 ;
        RECT 483.840 19.215 484.740 490.105 ;
        RECT 487.140 19.215 492.825 490.105 ;
  END
END crypto_aes
END LIBRARY

